VERSION 5.7 ;

BUSBITCHARS "[]" ;
DIVIDERCHAR "/" ;

UNITS
  DATABASE MICRONS 1000 ;
END UNITS

MANUFACTURINGGRID 0.005 ;

PROPERTYDEFINITIONS
  LAYER LEF58_TYPE STRING ;
END PROPERTYDEFINITIONS

SITE CoreSite
  CLASS CORE ;
  SYMMETRY Y ;
  SIZE 25 BY 25 ;
END CoreSite

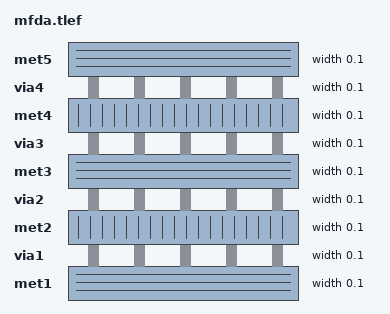
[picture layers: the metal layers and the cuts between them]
LAYER met1
  TYPE ROUTING ;
  DIRECTION HORIZONTAL ;
  MINWIDTH 0.1 ;
  WIDTH 0.1 ;
END met1

LAYER via1
  TYPE CUT ;
  WIDTH 0.1 ;
END via1

LAYER met2
  TYPE ROUTING ;
  DIRECTION VERTICAL ;
  MINWIDTH 0.1 ;
  WIDTH 0.1 ;
END met2

LAYER via2
  TYPE CUT ;
  WIDTH 0.1 ;
END via2

LAYER met3
  TYPE ROUTING ;
  DIRECTION HORIZONTAL ;
  MINWIDTH 0.1 ;
  WIDTH 0.1 ;
END met3

LAYER via3
  TYPE CUT ;
  WIDTH 0.1 ;
END via3

LAYER met4
  TYPE ROUTING ;
  DIRECTION VERTICAL ;
  MINWIDTH 0.1 ;
  WIDTH 0.1 ;
END met4

LAYER via4
  TYPE CUT ;
  WIDTH 0.1 ;
END via4

LAYER met5
  TYPE ROUTING ;
  DIRECTION HORIZONTAL ;
  MINWIDTH 0.1 ;
  WIDTH 0.1 ;
END met5

VIA M1M2_PR DEFAULT
  LAYER via1 ;
    RECT -0.05 -0.05 0.05 0.05 ;
  LAYER met1 ;
    RECT -0.05 -0.05 0.05 0.05 ;
  LAYER met2 ;
    RECT -0.05 -0.05 0.05 0.05 ;
END M1M2_PR

VIA M2M3_PR DEFAULT
  LAYER via2 ;
    RECT -0.05 -0.05 0.05 0.05 ;
  LAYER met2 ;
    RECT -0.05 -0.05 0.05 0.05 ;
  LAYER met3 ;
    RECT -0.05 -0.05 0.05 0.05 ;
END M2M3_PR

VIA M3M4_PR DEFAULT
  LAYER via3 ;
    RECT -0.05 -0.05 0.05 0.05 ;
  LAYER met3 ;
    RECT -0.05 -0.05 0.05 0.05 ;
  LAYER met4 ;
    RECT -0.05 -0.05 0.05 0.05 ;
END M3M4_PR

VIA M4M5_PR DEFAULT
  LAYER via4 ;
    RECT -0.05 -0.05 0.05 0.05 ;
  LAYER met4 ;
    RECT -0.05 -0.05 0.05 0.05 ;
  LAYER met5 ;
    RECT -0.05 -0.05 0.05 0.05 ;
END M4M5_PR

END LIBRARY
